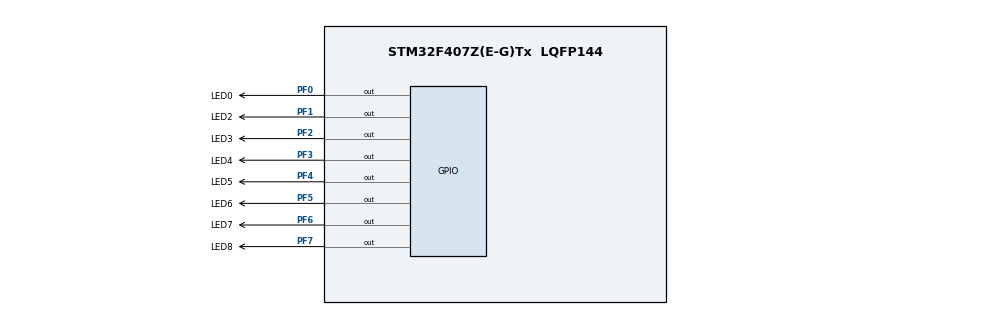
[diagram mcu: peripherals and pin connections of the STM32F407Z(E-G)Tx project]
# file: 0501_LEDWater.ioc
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Mcu.Family=STM32F4
Mcu.Name=STM32F407Z(E-G)Tx
Mcu.Package=LQFP144
NVIC.PriorityGroup=NVIC_PRIORITYGROUP_4
PA13.Mode=Serial_Wire
PA13.Signal=SYS_JTMS-SWDIO
PA14.Mode=Serial_Wire
PA14.Signal=SYS_JTCK-SWCLK
PF0.GPIO_Label=LED0
PF0.PinState=GPIO_PIN_SET
PF0.Signal=GPIO_Output
PF1.GPIO_Label=LED2
PF1.PinState=GPIO_PIN_SET
PF1.Signal=GPIO_Output
PF2.GPIO_Label=LED3
PF2.PinState=GPIO_PIN_SET
PF2.Signal=GPIO_Output
PF3.GPIO_Label=LED4
PF3.PinState=GPIO_PIN_SET
PF3.Signal=GPIO_Output
PF4.GPIO_Label=LED5
PF4.PinState=GPIO_PIN_SET
PF4.Signal=GPIO_Output
PF5.GPIO_Label=LED6
PF5.PinState=GPIO_PIN_SET
PF5.Signal=GPIO_Output
PF6.GPIO_Label=LED7
PF6.PinState=GPIO_PIN_SET
PF6.Signal=GPIO_Output
PF7.GPIO_Label=LED8
PF7.PinState=GPIO_PIN_SET
PF7.Signal=GPIO_Output
PH0-OSC_IN.Mode=HSE-External-Oscillator
PH0-OSC_IN.Signal=RCC_OSC_IN
PH1-OSC_OUT.Mode=HSE-External-Oscillator
PH1-OSC_OUT.Signal=RCC_OSC_OUT
ProjectManager.HeapSize=0x200
ProjectManager.StackSize=0x400
ProjectManager.TargetToolchain=MDK-ARM V5.32
RCC.48MHZClocksFreq_Value=84000000
RCC.AHBFreq_Value=168000000
RCC.APB1CLKDivider=RCC_HCLK_DIV4
RCC.APB1Freq_Value=42000000
RCC.APB1TimFreq_Value=84000000
RCC.APB2CLKDivider=RCC_HCLK_DIV8
RCC.APB2Freq_Value=21000000
RCC.APB2TimFreq_Value=42000000
RCC.CortexFreq_Value=168000000
RCC.HCLKFreq_Value=168000000
RCC.HSE_VALUE=8000000
RCC.HSI_VALUE=16000000
RCC.LSE_VALUE=32768
RCC.PLLM=8
RCC.PLLN=336
RCC.PLLSourceVirtual=RCC_PLLSOURCE_HSE
RCC.SYSCLKFreq_VALUE=168000000
RCC.SYSCLKSource=RCC_SYSCLKSOURCE_PLLCLK
RCC.VCOOutputFreq_Value=336000000
board=custom

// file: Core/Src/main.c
#include "main.h"

void SystemClock_Config(void);
static void MX_GPIO_Init(void);

/* USER CODE BEGIN 0 */
void delay(uint32_t i)
{
    while(i--);
}
/* USER CODE END 0 */

int main(void)
{

  /* MCU Configuration--------------------------------------------------------*/

  /* Reset of all peripherals, Initializes the Flash interface and the Systick. */
  HAL_Init();

  /* Configure the system clock */
  SystemClock_Config();

  /* Initialize all configured peripherals */
  MX_GPIO_Init();

  /* Infinite loop */
  /* USER CODE BEGIN WHILE */
  while (1)
  {
    GPIOF->ODR = 0xFE;
    delay(2400000);
    GPIOF->ODR = 0xFD;
    delay(2400000);
    GPIOF->ODR = 0xFB;
    delay(2400000);
    GPIOF->ODR = 0xF7;
    delay(2400000);
    GPIOF->ODR = 0xEF;
    delay(2400000);
    GPIOF->ODR = 0xDF;
    delay(2400000);
    GPIOF->ODR = 0xBF;
    delay(2400000);
    GPIOF->ODR = 0x7F;
    delay(2400000);
  }
  /* USER CODE END WHILE */

}

void SystemClock_Config(void)
{
  RCC_OscInitTypeDef RCC_OscInitStruct = {0};
  RCC_ClkInitTypeDef RCC_ClkInitStruct = {0};

  __HAL_RCC_PWR_CLK_ENABLE();
  __HAL_PWR_VOLTAGESCALING_CONFIG(PWR_REGULATOR_VOLTAGE_SCALE1);

  RCC_OscInitStruct.OscillatorType = RCC_OSCILLATORTYPE_HSE;
  RCC_OscInitStruct.HSEState = RCC_HSE_ON;
  RCC_OscInitStruct.PLL.PLLState = RCC_PLL_ON;
  RCC_OscInitStruct.PLL.PLLSource = RCC_PLLSOURCE_HSE;
  RCC_OscInitStruct.PLL.PLLM = 8;
  RCC_OscInitStruct.PLL.PLLN = 336;
  RCC_OscInitStruct.PLL.PLLP = RCC_PLLP_DIV2;
  RCC_OscInitStruct.PLL.PLLQ = 7;
  if (HAL_RCC_OscConfig(&RCC_OscInitStruct) != HAL_OK)
  {
    Error_Handler();
  }

  RCC_ClkInitStruct.ClockType = RCC_CLOCKTYPE_HCLK|RCC_CLOCKTYPE_SYSCLK
                              |RCC_CLOCKTYPE_PCLK1|RCC_CLOCKTYPE_PCLK2;
  RCC_ClkInitStruct.SYSCLKSource = RCC_SYSCLKSOURCE_PLLCLK;
  RCC_ClkInitStruct.AHBCLKDivider = RCC_SYSCLK_DIV1;
  RCC_ClkInitStruct.APB1CLKDivider = RCC_HCLK_DIV4;
  RCC_ClkInitStruct.APB2CLKDivider = RCC_HCLK_DIV2;

  if (HAL_RCC_ClockConfig(&RCC_ClkInitStruct, FLASH_LATENCY_5) != HAL_OK)
  {
    Error_Handler();
  }
}

static void MX_GPIO_Init(void)
{
  GPIO_InitTypeDef GPIO_InitStruct = {0};

  __HAL_RCC_GPIOF_CLK_ENABLE();

  HAL_GPIO_WritePin(GPIOF, GPIO_PIN_0|GPIO_PIN_1|GPIO_PIN_2|GPIO_PIN_3
                          |GPIO_PIN_4|GPIO_PIN_5|GPIO_PIN_6|GPIO_PIN_7, GPIO_PIN_SET);

  GPIO_InitStruct.Pin = GPIO_PIN_0|GPIO_PIN_1|GPIO_PIN_2|GPIO_PIN_3
                          |GPIO_PIN_4|GPIO_PIN_5|GPIO_PIN_6|GPIO_PIN_7;
  GPIO_InitStruct.Mode = GPIO_MODE_OUTPUT_PP;
  GPIO_InitStruct.Pull = GPIO_NOPULL;
  GPIO_InitStruct.Speed = GPIO_SPEED_FREQ_LOW;
  HAL_GPIO_Init(GPIOF, &GPIO_InitStruct);
}

void Error_Handler(void)
{
  __disable_irq();
  while (1)
  {
  }
}
